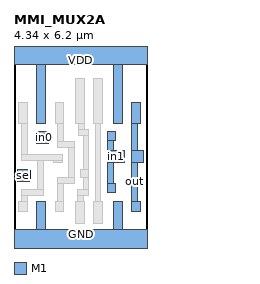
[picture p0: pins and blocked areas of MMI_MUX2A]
MACRO MMI_MUX2A
	CLASS CORE ;
	FOREIGN MMI_MUX2A 0 0 ;
	SIZE 4.34 BY 6.2 ;
	SYMMETRY X Y ;
	SITE CORE1 ;
	PIN out
		DIRECTION output ;
		USE SIGNAL ;
		PORT
			LAYER M1 ;
			RECT 3.835 3.855 4.115 4.555 ;
			LAYER M1 ;
			RECT 3.84 2.98 4.03 3.855 ;
			LAYER M1 ;
			RECT 3.84 2.6 4.22 2.98 ;
			LAYER M1 ;
			RECT 3.84 1.32 4.03 2.6 ;
			LAYER M1 ;
			RECT 3.835 1.005 4.115 1.32 ;
		END
		AntennaDiffArea 0.456225 ;
	END out
	PIN sel
		DIRECTION input ;
		USE SIGNAL ;
		PORT
			LAYER M1 ;
			RECT 0.12 1.98 0.5 2.36 ;
		END
		AntennaGateArea 0.40425 ;
	END sel
	PIN in1
		DIRECTION input ;
		USE SIGNAL ;
		PORT
			LAYER M1 ;
			RECT 3.035 3.32 3.315 3.6 ;
			LAYER M1 ;
			RECT 3.06 2.98 3.25 3.32 ;
			LAYER M1 ;
			RECT 3.06 2.6 3.6 2.98 ;
			LAYER M1 ;
			RECT 3.06 1.91 3.25 2.6 ;
			LAYER M1 ;
			RECT 3.035 1.63 3.315 1.91 ;
		END
		AntennaGateArea 0.17325 ;
	END in1
	PIN GND
		DIRECTION inout ;
		USE GROUND ;
		PORT
			LAYER M1 ;
			RECT 0.75 0.42 1.03 1.32 ;
			LAYER M1 ;
			RECT 3.245 0.42 3.525 1.32 ;
			LAYER M1 ;
			RECT 0 -0.42 4.34 0.42 ;
		END
	END GND
	PIN VDD
		DIRECTION inout ;
		USE POWER ;
		PORT
			LAYER M1 ;
			RECT 0 5.78 4.34 6.62 ;
			LAYER M1 ;
			RECT 0.75 3.855 1.03 5.78 ;
			LAYER M1 ;
			RECT 3.245 3.855 3.525 5.78 ;
		END
	END VDD
	PIN in0
		DIRECTION input ;
		USE SIGNAL ;
		PORT
			LAYER M1 ;
			RECT 0.74 3.555 1.12 3.6 ;
			LAYER M1 ;
			RECT 0.74 3.275 1.225 3.555 ;
			LAYER M1 ;
			RECT 0.74 3.22 1.12 3.275 ;
		END
		AntennaGateArea 0.17325 ;
	END in0
	OBS
		LAYER M1 ;
		RECT 0.155 3.855 0.435 4.555 ;
		LAYER M1 ;
		RECT 1.34 3.855 1.62 4.555 ;
		LAYER M1 ;
		RECT 2.005 3.855 2.285 5.325 ;
		LAYER M1 ;
		RECT 2.595 3.855 2.875 5.325 ;
		LAYER M1 ;
		RECT 0.245 2.87 0.435 3.855 ;
		LAYER M1 ;
		RECT 1.425 3.265 1.615 3.855 ;
		LAYER M1 ;
		RECT 2.09 3.655 2.285 3.855 ;
		LAYER M1 ;
		RECT 2.09 3.465 2.445 3.655 ;
		LAYER M1 ;
		RECT 1.425 3.075 1.96 3.265 ;
		LAYER M1 ;
		RECT 0.245 2.675 1.57 2.87 ;
		LAYER M1 ;
		RECT 0.775 1.715 0.97 2.675 ;
		LAYER M1 ;
		RECT 1.29 2.59 1.57 2.675 ;
		LAYER M1 ;
		RECT 1.77 2.11 1.96 3.075 ;
		LAYER M1 ;
		RECT 2.255 2.375 2.445 3.465 ;
		LAYER M1 ;
		RECT 0.245 1.52 0.97 1.715 ;
		LAYER M1 ;
		RECT 1.425 1.92 1.96 2.11 ;
		LAYER M1 ;
		RECT 2.165 2.095 2.445 2.375 ;
		LAYER M1 ;
		RECT 0.245 1.32 0.435 1.52 ;
		LAYER M1 ;
		RECT 1.425 1.32 1.615 1.92 ;
		LAYER M1 ;
		RECT 2.255 1.71 2.445 2.095 ;
		LAYER M1 ;
		RECT 2.085 1.52 2.445 1.71 ;
		LAYER M1 ;
		RECT 2.085 1.32 2.28 1.52 ;
		LAYER M1 ;
		RECT 2.645 1.32 2.835 3.855 ;
		LAYER M1 ;
		RECT 0.155 1.005 0.435 1.32 ;
		LAYER M1 ;
		RECT 1.34 1.005 1.62 1.32 ;
		LAYER M1 ;
		RECT 2.005 0.62 2.285 1.32 ;
		LAYER M1 ;
		RECT 2.595 0.62 2.875 1.32 ;
	END
END MMI_MUX2A
